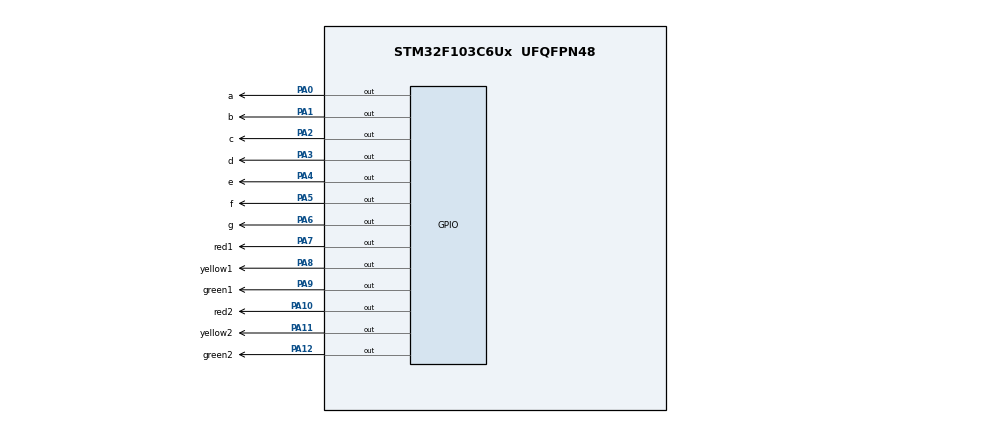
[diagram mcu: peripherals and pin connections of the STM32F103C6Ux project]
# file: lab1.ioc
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Mcu.Family=STM32F1
Mcu.Name=STM32F103C6Ux
Mcu.Package=UFQFPN48
NVIC.PriorityGroup=NVIC_PRIORITYGROUP_4
PA0-WKUP.GPIO_Label=a
PA0-WKUP.Signal=GPIO_Output
PA1.GPIO_Label=b
PA1.Signal=GPIO_Output
PA10.GPIO_Label=red2
PA10.PinState=GPIO_PIN_SET
PA10.Signal=GPIO_Output
PA11.GPIO_Label=yellow2
PA11.PinState=GPIO_PIN_SET
PA11.Signal=GPIO_Output
PA12.GPIO_Label=green2
PA12.Signal=GPIO_Output
PA2.GPIO_Label=c
PA2.Signal=GPIO_Output
PA3.GPIO_Label=d
PA3.Signal=GPIO_Output
PA4.GPIO_Label=e
PA4.Signal=GPIO_Output
PA5.GPIO_Label=f
PA5.PinState=GPIO_PIN_SET
PA5.Signal=GPIO_Output
PA6.GPIO_Label=g
PA6.PinState=GPIO_PIN_SET
PA6.Signal=GPIO_Output
PA7.GPIO_Label=red1
PA7.Signal=GPIO_Output
PA8.GPIO_Label=yellow1
PA8.PinState=GPIO_PIN_SET
PA8.Signal=GPIO_Output
PA9.GPIO_Label=green1
PA9.PinState=GPIO_PIN_SET
PA9.Signal=GPIO_Output
ProjectManager.HeapSize=0x200
ProjectManager.StackSize=0x400
ProjectManager.TargetToolchain=STM32CubeIDE
RCC.APB1Freq_Value=8000000
RCC.APB2Freq_Value=8000000
VP_SYS_VS_ND.Mode=No_Debug
board=custom

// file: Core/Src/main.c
/* USER CODE BEGIN Header */
/**
 ******************************************************************************
 * @file           : main.c
 * @brief          : Main program body
 ******************************************************************************
 * @attention
 *
 * <h2><center>&copy; Copyright (c) 2023 STMicroelectronics.
 * All rights reserved.</center></h2>
 *
 * This software component is licensed by ST under BSD 3-Clause license,
 * the "License"; You may not use this file except in compliance with the
 * License. You may obtain a copy of the License at:
 *                        opensource.org/licenses/BSD-3-Clause
 *
 ******************************************************************************
 */
/* USER CODE END Header */
#include "main.h"

/* USER CODE BEGIN Includes */
void writePin(int ptr, int state)
{
    if (ptr == 12)
        ptr = 0;
    if (state == 0)
    {
        if (ptr == 0)
            HAL_GPIO_WritePin(led12_GPIO_Port, led12_Pin, GPIO_PIN_SET);
        else if (ptr == 1)
            HAL_GPIO_WritePin(led1_GPIO_Port, led1_Pin, GPIO_PIN_SET);
        else if (ptr == 2)
            HAL_GPIO_WritePin(led2_GPIO_Port, led2_Pin, GPIO_PIN_SET);
        else if (ptr == 3)
            HAL_GPIO_WritePin(led3_GPIO_Port, led3_Pin, GPIO_PIN_SET);
        else if (ptr == 4)
            HAL_GPIO_WritePin(led4_GPIO_Port, led4_Pin, GPIO_PIN_SET);
        else if (ptr == 5)
            HAL_GPIO_WritePin(led5_GPIO_Port, led5_Pin, GPIO_PIN_SET);
        else if (ptr == 6)
            HAL_GPIO_WritePin(led6_GPIO_Port, led6_Pin, GPIO_PIN_SET);
        else if (ptr == 7)
            HAL_GPIO_WritePin(led7_GPIO_Port, led7_Pin, GPIO_PIN_SET);
        else if (ptr == 8)
            HAL_GPIO_WritePin(led8_GPIO_Port, led8_Pin, GPIO_PIN_SET);
        else if (ptr == 9)
            HAL_GPIO_WritePin(led9_GPIO_Port, led9_Pin, GPIO_PIN_SET);
        else if (ptr == 10)
            HAL_GPIO_WritePin(led10_GPIO_Port, led10_Pin, GPIO_PIN_SET);
        else if (ptr == 11)
            HAL_GPIO_WritePin(led11_GPIO_Port, led11_Pin, GPIO_PIN_SET);
    }
    else
    {
        if (ptr == 0)
            HAL_GPIO_WritePin(led12_GPIO_Port, led12_Pin, GPIO_PIN_RESET);
        else if (ptr == 1)
            HAL_GPIO_WritePin(led1_GPIO_Port, led1_Pin, GPIO_PIN_RESET);
        else if (ptr == 2)
            HAL_GPIO_WritePin(led2_GPIO_Port, led2_Pin, GPIO_PIN_RESET);
        else if (ptr == 3)
            HAL_GPIO_WritePin(led3_GPIO_Port, led3_Pin, GPIO_PIN_RESET);
        else if (ptr == 4)
            HAL_GPIO_WritePin(led4_GPIO_Port, led4_Pin, GPIO_PIN_RESET);
        else if (ptr == 5)
            HAL_GPIO_WritePin(led5_GPIO_Port, led5_Pin, GPIO_PIN_RESET);
        else if (ptr == 6)
            HAL_GPIO_WritePin(led6_GPIO_Port, led6_Pin, GPIO_PIN_RESET);
        else if (ptr == 7)
            HAL_GPIO_WritePin(led7_GPIO_Port, led7_Pin, GPIO_PIN_RESET);
        else if (ptr == 8)
            HAL_GPIO_WritePin(led8_GPIO_Port, led8_Pin, GPIO_PIN_RESET);
        else if (ptr == 9)
            HAL_GPIO_WritePin(led9_GPIO_Port, led9_Pin, GPIO_PIN_RESET);
        else if (ptr == 10)
            HAL_GPIO_WritePin(led10_GPIO_Port, led10_Pin, GPIO_PIN_RESET);
        else if (ptr == 11)
            HAL_GPIO_WritePin(led11_GPIO_Port, led11_Pin, GPIO_PIN_RESET);
    }
}
void clearAllClock()
{
    for (int i = 0; i < 11; i++)
    {
        writePin(i, 0);
    }
}

void setNumberOnClock(int num)
{
    if (num >= 0 && num <= 11)
        writePin(num, 1);
}

void clearNumberOnClock(int num)
{
    if (num >= 0 && num <= 11)
        writePin(num, 0);
}
/* USER CODE END Includes */

void SystemClock_Config(void);
static void MX_GPIO_Init(void);

int main(void)
{

    /* MCU Configuration--------------------------------------------------------*/

    /* Reset of all peripherals, Initializes the Flash interface and the Systick. */
    HAL_Init();

    /* Configure the system clock */
    SystemClock_Config();

    /* Initialize all configured peripherals */
    MX_GPIO_Init();
    int sec = 0, min = 0, hr = 0;
    int led_sec[12] = {0};
    int led_min[12] = {0};
    int led_hr[12] = {0};
    led_sec[0] = 1;
    led_min[0] = 1;
    led_hr[0] = 1;
    int curr = 0, prev = 11;
    /* Infinite loop */
    while (1)
    {
        int sec = 0, min = 0, hr = 0;
        while (1)
        {
            if (sec > 59)
            {
                sec = 0;
                min++;
            }
            if (min > 59)
            {
                min = 0;
                hr++;
            }
            if (hr > 11)
                hr = 0;
            sec++;
            clearAllClock();
            setNumberOnClock(sec / 5);
            setNumberOnClock(min / 5);
            setNumberOnClock(hr);
            HAL_Delay(1000);
        }
    }
}

void SystemClock_Config(void)
{
    RCC_OscInitTypeDef RCC_OscInitStruct = {0};
    RCC_ClkInitTypeDef RCC_ClkInitStruct = {0};

    /** Initializes the RCC Oscillators according to the specified parameters
     * in the RCC_OscInitTypeDef structure.
     */
    RCC_OscInitStruct.OscillatorType = RCC_OSCILLATORTYPE_HSI;
    RCC_OscInitStruct.HSIState = RCC_HSI_ON;
    RCC_OscInitStruct.HSICalibrationValue = RCC_HSICALIBRATION_DEFAULT;
    RCC_OscInitStruct.PLL.PLLState = RCC_PLL_NONE;
    if (HAL_RCC_OscConfig(&RCC_OscInitStruct) != HAL_OK)
    {
        Error_Handler();
    }
    /** Initializes the CPU, AHB and APB buses clocks
     */
    RCC_ClkInitStruct.ClockType = RCC_CLOCKTYPE_HCLK | RCC_CLOCKTYPE_SYSCLK | RCC_CLOCKTYPE_PCLK1 | RCC_CLOCKTYPE_PCLK2;
    RCC_ClkInitStruct.SYSCLKSource = RCC_SYSCLKSOURCE_HSI;
    RCC_ClkInitStruct.AHBCLKDivider = RCC_SYSCLK_DIV1;
    RCC_ClkInitStruct.APB1CLKDivider = RCC_HCLK_DIV1;
    RCC_ClkInitStruct.APB2CLKDivider = RCC_HCLK_DIV1;

    if (HAL_RCC_ClockConfig(&RCC_ClkInitStruct, FLASH_LATENCY_0) != HAL_OK)
    {
        Error_Handler();
    }
}

static void MX_GPIO_Init(void)
{
    GPIO_InitTypeDef GPIO_InitStruct = {0};

    /* GPIO Ports Clock Enable */
    __HAL_RCC_GPIOA_CLK_ENABLE();

    /*Configure GPIO pin Output Level */
    HAL_GPIO_WritePin(GPIOA, led1_Pin | led2_Pin | led3_Pin | led4_Pin | led5_Pin | led6_Pin | led7_Pin | led8_Pin | led9_Pin | led10_Pin | led11_Pin, GPIO_PIN_SET);

    /*Configure GPIO pin Output Level */
    HAL_GPIO_WritePin(led12_GPIO_Port, led12_Pin, GPIO_PIN_RESET);

    /*Configure GPIO pins : led1_Pin led2_Pin led3_Pin led4_Pin
                             led5_Pin led6_Pin led7_Pin led8_Pin
                             led9_Pin led10_Pin led11_Pin led12_Pin */
    GPIO_InitStruct.Pin = led1_Pin | led2_Pin | led3_Pin | led4_Pin | led5_Pin | led6_Pin | led7_Pin | led8_Pin | led9_Pin | led10_Pin | led11_Pin | led12_Pin;
    GPIO_InitStruct.Mode = GPIO_MODE_OUTPUT_PP;
    GPIO_InitStruct.Pull = GPIO_NOPULL;
    GPIO_InitStruct.Speed = GPIO_SPEED_FREQ_LOW;
    HAL_GPIO_Init(GPIOA, &GPIO_InitStruct);
}

void Error_Handler(void)
{
    __disable_irq();
    while (1)
    {
    }
}

/************************ (C) COPYRIGHT STMicroelectronics *****END OF FILE****/
